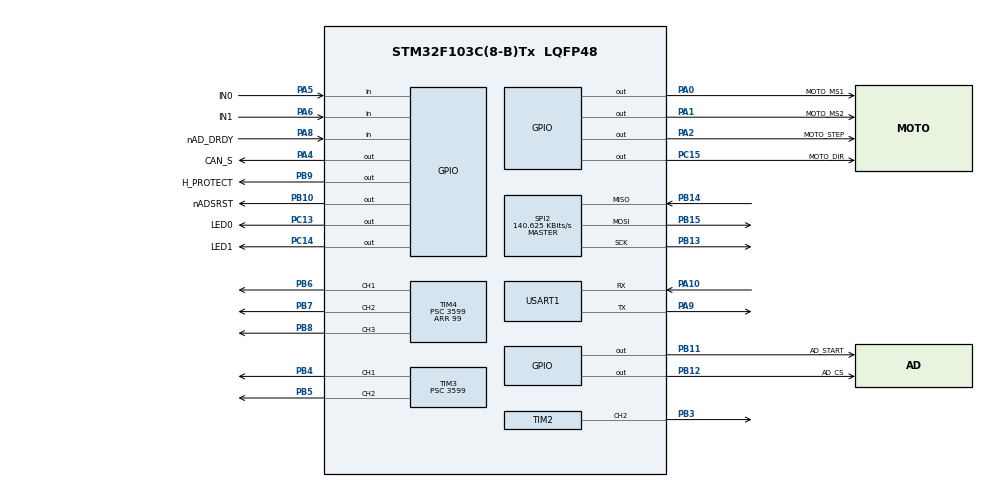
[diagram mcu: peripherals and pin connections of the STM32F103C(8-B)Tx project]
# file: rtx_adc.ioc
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Mcu.Family=STM32F1
Mcu.Name=STM32F103C(8-B)Tx
Mcu.Package=LQFP48
NVIC.PriorityGroup=NVIC_PRIORITYGROUP_2
NVIC.TIM1_UP_IRQn=true\:0\:0\:false\:false\:true
NVIC.TIM2_IRQn=true\:0\:0\:false\:false\:true
NVIC.TIM3_IRQn=true\:0\:0\:false\:false\:true
NVIC.TIM4_IRQn=true\:0\:0\:false\:false\:true
PA0-WKUP.GPIO_Label=MOTO_MS1
PA0-WKUP.GPIO_ModeDefaultOutputPP=GPIO_MODE_OUTPUT_PP
PA0-WKUP.GPIO_Speed=GPIO_SPEED_FREQ_HIGH
PA0-WKUP.Signal=GPIO_Output
PA1.GPIO_Label=MOTO_MS2
PA1.GPIO_ModeDefaultOutputPP=GPIO_MODE_OUTPUT_PP
PA1.GPIO_Speed=GPIO_SPEED_FREQ_HIGH
PA1.Signal=GPIO_Output
PA10.Mode=Asynchronous
PA10.Signal=USART1_RX
PA13.Mode=Serial_Wire
PA13.Signal=SYS_JTMS-SWDIO
PA14.Mode=Serial_Wire
PA14.Signal=SYS_JTCK-SWCLK
PA2.GPIO_Label=MOTO_STEP
PA2.GPIO_ModeDefaultOutputPP=GPIO_MODE_OUTPUT_PP
PA2.GPIO_Speed=GPIO_SPEED_FREQ_HIGH
PA2.Signal=GPIO_Output
PA4.GPIO_Label=CAN_S
PA4.GPIO_ModeDefaultOutputPP=GPIO_MODE_OUTPUT_PP
PA4.GPIO_Speed=GPIO_SPEED_FREQ_LOW
PA4.Signal=GPIO_Output
PA5.GPIO_Label=IN0
PA5.GPIO_Mode=GPIO_MODE_INPUT
PA5.GPIO_PuPd=GPIO_NOPULL
PA5.Signal=GPIO_Input
PA6.GPIO_Label=IN1
PA6.GPIO_Mode=GPIO_MODE_INPUT
PA6.GPIO_PuPd=GPIO_NOPULL
PA6.Signal=GPIO_Input
PA8.GPIO_Label=nAD_DRDY
PA8.GPIO_Mode=GPIO_MODE_INPUT
PA8.GPIO_PuPd=GPIO_NOPULL
PA8.Signal=GPIO_Input
PA9.Mode=Asynchronous
PA9.Signal=USART1_TX
PB10.GPIO_Label=nADSRST
PB10.GPIO_ModeDefaultOutputPP=GPIO_MODE_OUTPUT_PP
PB10.GPIO_Speed=GPIO_SPEED_FREQ_LOW
PB10.Signal=GPIO_Output
PB11.GPIO_Label=AD_START
PB11.GPIO_ModeDefaultOutputPP=GPIO_MODE_OUTPUT_PP
PB11.GPIO_Speed=GPIO_SPEED_FREQ_LOW
PB11.Signal=GPIO_Output
PB12.GPIO_Label=AD_CS
PB12.GPIO_ModeDefaultOutputPP=GPIO_MODE_OUTPUT_PP
PB12.GPIO_Speed=GPIO_SPEED_FREQ_LOW
PB12.Signal=GPIO_Output
PB13.Mode=Full_Duplex_Master
PB13.Signal=SPI2_SCK
PB14.Mode=Full_Duplex_Master
PB14.Signal=SPI2_MISO
PB15.Mode=Full_Duplex_Master
PB15.Signal=SPI2_MOSI
PB3.Signal=S_TIM2_CH2
PB4.Signal=S_TIM3_CH1
PB5.Signal=S_TIM3_CH2
PB6.Signal=S_TIM4_CH1
PB7.Signal=S_TIM4_CH2
PB8.Signal=S_TIM4_CH3
PB9.GPIO_Label=H_PROTECT
PB9.GPIO_ModeDefaultOutputPP=GPIO_MODE_OUTPUT_PP
PB9.GPIO_Speed=GPIO_SPEED_FREQ_LOW
PB9.Signal=GPIO_Output
PC13-TAMPER-RTC.GPIO_Label=LED0
PC13-TAMPER-RTC.GPIO_ModeDefaultOutputPP=GPIO_MODE_OUTPUT_PP
PC13-TAMPER-RTC.GPIO_Speed=GPIO_SPEED_FREQ_LOW
PC13-TAMPER-RTC.Signal=GPIO_Output
PC14-OSC32_IN.GPIO_Label=LED1
PC14-OSC32_IN.GPIO_ModeDefaultOutputPP=GPIO_MODE_OUTPUT_PP
PC14-OSC32_IN.GPIO_Speed=GPIO_SPEED_FREQ_LOW
PC14-OSC32_IN.Signal=GPIO_Output
PC15-OSC32_OUT.GPIO_Label=MOTO_DIR
PC15-OSC32_OUT.GPIO_ModeDefaultOutputPP=GPIO_MODE_OUTPUT_PP
PC15-OSC32_OUT.GPIO_Speed=GPIO_SPEED_FREQ_HIGH
PC15-OSC32_OUT.Signal=GPIO_Output
PD0-OSC_IN.Mode=HSE-External-Oscillator
PD0-OSC_IN.Signal=RCC_OSC_IN
PD1-OSC_OUT.Mode=HSE-External-Oscillator
PD1-OSC_OUT.Signal=RCC_OSC_OUT
ProjectManager.HeapSize=0x200
ProjectManager.StackSize=0x400
ProjectManager.TargetToolchain=MDK-ARM V4
RCC.AHBFreq_Value=72000000
RCC.APB1CLKDivider=RCC_HCLK_DIV2
RCC.APB1Freq_Value=36000000
RCC.APB1TimFreq_Value=72000000
RCC.APB2Freq_Value=72000000
RCC.APB2TimFreq_Value=72000000
RCC.HCLKFreq_Value=72000000
RCC.HSIState=RCC_HSI_ON
RCC.PLLMUL=RCC_PLL_MUL9
RCC.PLLSourceVirtual=RCC_PLLSOURCE_HSE
RCC.SYSCLKFreq_VALUE=72000000
RCC.SYSCLKSource=RCC_SYSCLKSOURCE_PLLCLK
RCC.USBFreq_Value=72000000
SH.S_TIM2_CH2.0=TIM2_CH2,PWM Generation2 CH2
SH.S_TIM3_CH1.0=TIM3_CH1,PWM Generation1 CH1
SH.S_TIM3_CH2.0=TIM3_CH2,PWM Generation2 CH2
SH.S_TIM4_CH1.0=TIM4_CH1,PWM Generation1 CH1
SH.S_TIM4_CH2.0=TIM4_CH2,PWM Generation2 CH2
SH.S_TIM4_CH3.0=TIM4_CH3,PWM Generation3 CH3
SPI2.BaudRatePrescaler=SPI_BAUDRATEPRESCALER_256
SPI2.CLKPolarity=SPI_POLARITY_HIGH
SPI2.CalculateBaudRate=140.625 KBits/s
SPI2.Mode=SPI_MODE_MASTER
TIM1.Period=999
TIM1.Prescaler=71
TIM2.Channel-PWM\ Generation2\ CH2=TIM_CHANNEL_2
TIM2.OCFastMode_PWM-PWM\ Generation2\ CH2=TIM_OCFAST_ENABLE
TIM2.OCMode_PWM-PWM\ Generation2\ CH2=TIM_OCMODE_PWM1
TIM2.OCPolarity_2=TIM_OCPOLARITY_LOW
TIM2.Period=99
TIM2.Prescaler=3599
TIM2.Pulse-PWM\ Generation2\ CH2=49
TIM3.Channel-PWM\ Generation2\ CH2=TIM_CHANNEL_2
TIM3.OCPolarity_1=TIM_OCPOLARITY_LOW
TIM3.OCPolarity_2=TIM_OCPOLARITY_LOW
TIM3.Period=99
TIM3.Prescaler=3599
TIM3.Pulse-PWM\ Generation1\ CH1=49
TIM3.Pulse-PWM\ Generation2\ CH2=49
TIM4.Channel=TIM_CHANNEL_2
TIM4.Channel-PWM\ Generation2\ CH2=TIM_CHANNEL_2
TIM4.Channel-PWM\ Generation3\ CH3=TIM_CHANNEL_3
TIM4.OCPolarity_1=TIM_OCPOLARITY_LOW
TIM4.OCPolarity_2=TIM_OCPOLARITY_LOW
TIM4.OCPolarity_3=TIM_OCPOLARITY_LOW
TIM4.Period=99
TIM4.Prescaler=3599
TIM4.Pulse-PWM\ Generation1\ CH1=49
TIM4.Pulse-PWM\ Generation2\ CH2=49
TIM4.Pulse-PWM\ Generation3\ CH3=49
VP_TIM1_VS_ClockSourceINT.Mode=Internal
VP_TIM2_VS_ClockSourceINT.Mode=Internal
VP_TIM4_VS_ClockSourceINT.Mode=Internal
board=rtx_adc

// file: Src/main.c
/**
  ******************************************************************************
  * File Name          : main.c
  * Description        : Main program body
  ******************************************************************************
  *
  * COPYRIGHT(c) 2016 STMicroelectronics
  *
  * Redistribution and use in source and binary forms, with or without modification,
  * are permitted provided that the following conditions are met:
  *   1. Redistributions of source code must retain the above copyright notice,
  *      this list of conditions and the following disclaimer.
  *   2. Redistributions in binary form must reproduce the above copyright notice,
  *      this list of conditions and the following disclaimer in the documentation
  *      and/or other materials provided with the distribution.
  *   3. Neither the name of STMicroelectronics nor the names of its contributors
  *      may be used to endorse or promote products derived from this software
  *      without specific prior written permission.
  *
  * THIS SOFTWARE IS PROVIDED BY THE COPYRIGHT HOLDERS AND CONTRIBUTORS "AS IS"
  * AND ANY EXPRESS OR IMPLIED WARRANTIES, INCLUDING, BUT NOT LIMITED TO, THE
  * IMPLIED WARRANTIES OF MERCHANTABILITY AND FITNESS FOR A PARTICULAR PURPOSE ARE
  * DISCLAIMED. IN NO EVENT SHALL THE COPYRIGHT HOLDER OR CONTRIBUTORS BE LIABLE
  * FOR ANY DIRECT, INDIRECT, INCIDENTAL, SPECIAL, EXEMPLARY, OR CONSEQUENTIAL
  * DAMAGES (INCLUDING, BUT NOT LIMITED TO, PROCUREMENT OF SUBSTITUTE GOODS OR
  * SERVICES; LOSS OF USE, DATA, OR PROFITS; OR BUSINESS INTERRUPTION) HOWEVER
  * CAUSED AND ON ANY THEORY OF LIABILITY, WHETHER IN CONTRACT, STRICT LIABILITY,
  * OR TORT (INCLUDING NEGLIGENCE OR OTHERWISE) ARISING IN ANY WAY OUT OF THE USE
  * OF THIS SOFTWARE, EVEN IF ADVISED OF THE POSSIBILITY OF SUCH DAMAGE.
  *
  ******************************************************************************
  */
#include "stm32f1xx_hal.h"
#include "spi.h"
#include "tim.h"
#include "usart.h"
#include "gpio.h"

/* USER CODE BEGIN Includes */
#include <RTL.h>
#include "ADS1248.h"
#include "step_motor_driver.h"
#include "pid_driver.h"
/* USER CODE END Includes */

/* USER CODE BEGIN PV */
/* Private variables ---------------------------------------------------------*/
OS_TID t_adc;                        /* assigned task id of task: adcTask */
OS_TID t_printf;                        /* assigned task id of task: printfTask */
OS_TID t_motor;                        /* assigned task id of task: motorTask */
OS_TID t_test;                        /* assigned task id of task: testTask */
volatile uint32_t chanelDataArray[7];												/* AD数据 */
volatile float chanelTempArray[7]; 				/* 各通道温度数组 */
const float chanelDrift[7] = { 0.6, 0.25, -0.3, -0.35, 0, 0, -0.3 };
static PID PID_Chanel[7];

/* USER CODE END PV */

void SystemClock_Config(void);
void Error_Handler(void);

/* USER CODE BEGIN PFP */
/* Private function prototypes -----------------------------------------------*/

/* USER CODE END PFP */

/* USER CODE BEGIN 0 */

/**
  * @brief  步进电机控制测试任务.
  * @param  None.
  * @note   两个静态变量分别用于控制电机步进控制与电机配置控制.
	*      @arg openTIM: 0表示中断未开启，1表示中断已开启
	*      @arg microStep: 0、1、2、3分别代表细分级数：FULL、HALF、QUARTER、EIGHTH
	*           每次切换细分级数时同时修改电机转动方向。
	*						 FULL   -> 200节拍(一圈)  (顺时针旋转)
	*						 HALF   -> 400节拍(一圈)  (逆时针旋转)
	*						 FOUTH  -> 800节拍(一圈)  (顺时针旋转)
	*						 EIGTH  -> 1600节拍(一圈) (逆时针旋转)
  * @retval None
  */
__task void motorTask (void) {
	BSP_STEP_MOTOR_Init();			// 初始化电机
	uint8_t openTIM = 1; // 默认初始化时Step为0，此时计时器中断应该为关闭状态，这里为了进行测试设置为1
	uint8_t microStep = 0;	// 细分步数标志
  for (;;) {
		if(openTIM == 0 && STEP_MOTOR_Msg.Step > 0)	// 当Step>0且计时器处于关闭状态时开启计时器
		{
			HAL_TIM_Base_Start_IT(&htim1);
			openTIM=1;
		}
		if(openTIM == 1 && STEP_MOTOR_Msg.Step == 0)	// 当计时器处于开启状态且Step已为0时设置计时器标志位为1
		{
			openTIM = 0;
			os_dly_wait(100);
			switch(microStep)
			{
				case 0: // FULL FORWARD
					STEP_MOTOR_Msg.Dir = FORWARD;
					STEP_MOTOR_Msg.MicroStep = FULL;
					STEP_MOTOR_Msg.Step = 200;
					microStep++;
					break;
				case 1:	// HALF REVERSAL
					STEP_MOTOR_Msg.Dir = REVERSAL;
					STEP_MOTOR_Msg.MicroStep = HALF;
					STEP_MOTOR_Msg.Step = 400;
					microStep++;
					break;
				case 2: // QUARTER FORWARD
					STEP_MOTOR_Msg.Dir = FORWARD;
					STEP_MOTOR_Msg.MicroStep = QUARTER;
					STEP_MOTOR_Msg.Step = 800;
					microStep++;
					break;
				case 3: // EIGHTH REVERSAL
					STEP_MOTOR_Msg.Dir = REVERSAL;
					STEP_MOTOR_Msg.MicroStep = EIGHTH;
					STEP_MOTOR_Msg.Step = 1600;
					microStep = 0;
					break;
				default:
					break;
			}
		}
		os_tsk_pass();//上述判断条件语句执行完成后交出CPU控制权
  }
}

/**
  * @brief  测试任务.
  * @param  None.
  * @note   设置LED1每秒闪烁一次.
  * @retval None
  */
__task void testTask (void) {
  for (;;) {
		HAL_GPIO_TogglePin(GPIOC,GPIO_PIN_13);
		os_dly_wait(1000);
  }
}

/**
  * @brief  打印任务，用于打印串口数据.
  * @param  None.
  * @note   当前仅打印AD值及与其对应的温度值
  * @retval None
  */
__task void printfTask (void) {

  for (;;) {

		int i;
		float Temp;
		for(i=0; i<7; i++)
		{
			// R = Ad/Full/Gain*2*Rref+R2
//			R = chanelDataArray[i]/0x7fffff/8*2*810+180;
			Temp = ADS1248_AdToTemp(chanelDataArray[i]);//直接根据AD值查表得到温度值
			printf("%5.2d ,  %4.2f  ;", chanelDataArray[i], Temp);

		}
		printf("\n");
		os_dly_wait(100);
  }
}

/**
  * @brief  ADC及PID测试任务.
  * @param  None.
  * @note   循环获取7个AD通道的AD值，并将AD值存储至数组中
	* 				根据转换得到的温度值进性PID控制
	* 				chanel:通道编号
	* 				PIDSet[7]:标识各通道PID控制时间间隔
	*					chanelDataArray[7]：存储各通道AD值
	*					chanelTempArray[7]：存储各通道AD值对应的温度值
  * @retval None
  */
__task void adcTask (void) {
	int i;
	for(i=0; i<7; i++)//PID初始化
	{
		PID_Init(&PID_Chanel[i]);
		//PID配置，设置各通道Kp,Ki,Kd值，SetPoint值应该在设置温度时进性配置，此处用于测试对其进行配置
		PID_SetPoint(&PID_Chanel[i], 40); //设置 PID 调节的目标值
		PID_SetKp(&PID_Chanel[i], 2); //设置 PID 的 Kp 值
		PID_SetKi(&PID_Chanel[i], 0); //设置 PID 的 Ki 值
		PID_SetKd(&PID_Chanel[i], 0); //设置 PID 的 Kd 值
	}

	os_dly_wait(17);
	ADS1248_Init(ADC_GAIN_16|ADC_SPS_20);             //初始化 AD1248
	int8_t chanel = 0;
	int16_t PIDSet[7] = { 0, 0, 0, 0, 0, 0, 0 };
  for (;;) {
	int32_t Data;

	Data = ADS1248_Channel_Data(chanel);
	chanelTempArray[chanel] = ADS1248_AdToTemp(Data);

	if(PIDSet[chanel] == 30) // 间隔指定时间进入一次PID控制
	{
		/*如果当前温度与设定值相差50度，则进入PID控制范围*/
		if( (PID_Chanel[chanel].SetPoint - chanelTempArray[chanel] < 50 && PID_Chanel[chanel].SetPoint - chanelTempArray[chanel] > 0)
				|| (PID_Chanel[chanel].SetPoint - chanelTempArray[chanel] > -50 && PID_Chanel[chanel].SetPoint - chanelTempArray[chanel] < 0))
		{
			uint8_t pulse = PID_IncCalc(&PID_Chanel[chanel],chanelTempArray[chanel]);//采用PID增量模式
			printf("puse%d: %d,  temp: %f\n",chanel, pulse, chanelTempArray[chanel]);
			PID_IncPWMCtr(chanel, pulse);//增量式PID的PWM控制
		}
		PIDSet[chanel] = 0;

	}

	chanelDataArray[chanel] = Data;
	PIDSet[chanel]++;
	chanel++;
	if(chanel==7)
	{
		chanel=0;
	};
	os_dly_wait(10);

  }
}

/**
  * @brief  初始化任务.
  * @param  None.
  * @note   用于创建任务，当任务都创建完成时，其使命达成自行销毁.
  * @retval None
  */
__task void initTask (void) {
	t_adc = os_tsk_create(adcTask,1);
	t_printf = os_tsk_create(printfTask,1);
	t_motor = os_tsk_create(motorTask,1);
	t_test = os_tsk_create(testTask,1);
	os_tsk_delete_self();
}
/* USER CODE END 0 */

int main(void)
{

  /* MCU Configuration----------------------------------------------------------*/

  /* Reset of all peripherals, Initializes the Flash interface and the Systick. */
  HAL_Init();

  /* Configure the system clock */
  SystemClock_Config();

  /* Initialize all configured peripherals */
  MX_GPIO_Init();
  MX_SPI2_Init();
  MX_TIM1_Init();
  MX_TIM2_Init();
  MX_TIM3_Init();
  MX_TIM4_Init();
  MX_USART1_UART_Init();

  /* USER CODE BEGIN 2 */

	HAL_TIM_PWM_Start_IT(&htim2,TIM_CHANNEL_2);

	HAL_TIM_PWM_Start_IT(&htim3,TIM_CHANNEL_1);
	HAL_TIM_PWM_Start_IT(&htim3,TIM_CHANNEL_2);

	HAL_TIM_PWM_Start_IT(&htim4,TIM_CHANNEL_1);
	HAL_TIM_PWM_Start_IT(&htim4,TIM_CHANNEL_2);
	HAL_TIM_PWM_Start_IT(&htim4,TIM_CHANNEL_3);

	// 初始化RTX内核并启动初始化任务，此后应用程序将在任务中继续执行
//	os_sys_init(initTask);
	os_sys_init_prio(initTask,3);
  /* USER CODE END 2 */

  /* Infinite loop */
  while (1)
  {

  }

}

/** System Clock Configuration
*/
void SystemClock_Config(void)
{

  RCC_OscInitTypeDef RCC_OscInitStruct;
  RCC_ClkInitTypeDef RCC_ClkInitStruct;

  RCC_OscInitStruct.OscillatorType = RCC_OSCILLATORTYPE_HSE;
  RCC_OscInitStruct.HSEState = RCC_HSE_ON;
  RCC_OscInitStruct.HSEPredivValue = RCC_HSE_PREDIV_DIV1;
  RCC_OscInitStruct.PLL.PLLState = RCC_PLL_ON;
  RCC_OscInitStruct.PLL.PLLSource = RCC_PLLSOURCE_HSE;
  RCC_OscInitStruct.PLL.PLLMUL = RCC_PLL_MUL9;
  if (HAL_RCC_OscConfig(&RCC_OscInitStruct) != HAL_OK)
  {
    Error_Handler();
  }

  RCC_ClkInitStruct.ClockType = RCC_CLOCKTYPE_HCLK|RCC_CLOCKTYPE_SYSCLK
                              |RCC_CLOCKTYPE_PCLK1|RCC_CLOCKTYPE_PCLK2;
  RCC_ClkInitStruct.SYSCLKSource = RCC_SYSCLKSOURCE_PLLCLK;
  RCC_ClkInitStruct.AHBCLKDivider = RCC_SYSCLK_DIV1;
  RCC_ClkInitStruct.APB1CLKDivider = RCC_HCLK_DIV4;
  RCC_ClkInitStruct.APB2CLKDivider = RCC_HCLK_DIV1;
  if (HAL_RCC_ClockConfig(&RCC_ClkInitStruct, FLASH_LATENCY_2) != HAL_OK)
  {
    Error_Handler();
  }

  HAL_SYSTICK_Config(HAL_RCC_GetHCLKFreq()/1000);

  HAL_SYSTICK_CLKSourceConfig(SYSTICK_CLKSOURCE_HCLK);

  /* SysTick_IRQn interrupt configuration */
  HAL_NVIC_SetPriority(SysTick_IRQn, 0, 0);
}

/* USER CODE BEGIN 4 */
int fputc(int ch,FILE *f)
{
    uint8_t temp[1]={ch};
    HAL_UART_Transmit(&huart1,temp,1,2);
		return ch;
}
/* USER CODE END 4 */

void Error_Handler(void)
{
  while(1)
  {
  }
}

/************************ (C) COPYRIGHT STMicroelectronics *****END OF FILE****/
